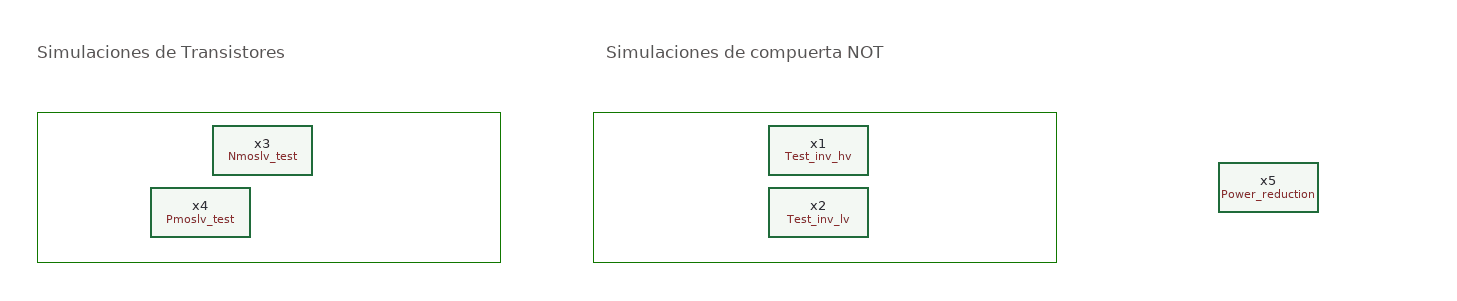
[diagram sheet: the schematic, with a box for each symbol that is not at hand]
v {xschem version=3.4.5 file_version=1.2
}
G {}
K {}
V {}
S {}
E {}
L 4 -180 -50 -180 40 {}
L 4 -180 -50 190 -50 {}
L 4 190 -50 190 40 {}
L 4 190 40 190 60 {}
L 4 190 60 190 70 {}
L 4 -180 70 190 70 {}
L 4 -180 40 -180 70 {}
L 4 -625 -50 -625 40 {}
L 4 -625 -50 -255 -50 {}
L 4 -255 -50 -255 40 {}
L 4 -255 40 -255 60 {}
L 4 -255 60 -255 70 {}
L 4 -625 70 -255 70 {}
L 4 -625 40 -625 70 {}
T {Simulaciones de compuerta NOT} -170 -110 0 0 0.4 0.4 {}
T {Simulaciones de Transistores
} -625 -110 0 0 0.4 0.4 {}
C {Resuelto/Test_inv_hv.sym} 0 -20 0 0 {name=x1}
C {Resuelto/Test_inv_lv.sym} 0 30 0 0 {name=x2}
C {title.sym} -480 160 0 0 {name=l1 author="Taller 1 ChipUSM"}
C {Resuelto/Pmoslv_test.sym} -495 30 0 0 {name=x4}
C {Resuelto/Nmoslv_test.sym} -445 -20 0 0 {name=x3}
C {/workspaces/usm-vlsi-tools/shared_xserver/Talleres/Taller1/Insumos/Power_reduction.sym} 360 10 0 0 {name=x5}
